VERSION 5.7 ;
BUSBITCHARS "[]" ;
DIVIDERCHAR "/" ;

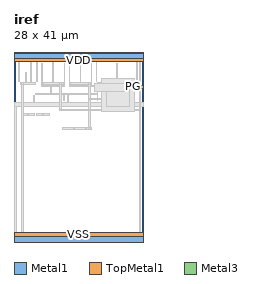
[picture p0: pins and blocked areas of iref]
MACRO iref
  CLASS BLOCK ;
  FOREIGN iref ;
  ORIGIN 0.000 0.000 ;
  SIZE 28.000 BY 41.000 ;
  PIN VDD
    DIRECTION INOUT ;
    USE POWER ;
    PORT
      LAYER Metal1 ;
        RECT 0.000 39.500 28.000 40.700 ;
      LAYER TopMetal1 ;
        RECT 0.000 39.000 28.000 41.000 ;
    END
  END VDD
  PIN VSS
    DIRECTION INOUT ;
    USE GROUND ;
    PORT
      LAYER Metal1 ;
        RECT 0.000 0.000 28.000 1.200 ;
      LAYER TopMetal1 ;
        RECT 0.000 0.000 28.000 2.000 ;
    END
  END VSS
  PIN PG
    DIRECTION OUTPUT ;
    USE SIGNAL ;
    ANTENNADIFFAREA 2.28 ;
    PORT
      LAYER Metal3 ;
        RECT 27.400 33.200 28.000 33.700 ;
    END
  END PG
  OBS
      LAYER Metal1 ;
        RECT 1.610 1.770 2.070 2.070 ;
        RECT 2.410 1.770 3.670 2.070 ;
        RECT 4.010 1.770 5.270 2.070 ;
        RECT 5.610 1.770 6.870 2.070 ;
        RECT 7.210 1.200 7.670 2.070 ;
        RECT 10.520 1.200 11.480 2.070 ;
        RECT 11.820 1.770 14.080 2.070 ;
        RECT 14.420 1.770 16.680 2.070 ;
        RECT 18.110 1.200 18.570 2.070 ;
        RECT 18.910 1.770 20.170 2.070 ;
        RECT 20.510 1.770 21.770 2.070 ;
        RECT 22.110 1.770 23.370 2.070 ;
        RECT 23.710 1.770 24.970 2.070 ;
        RECT 25.310 1.770 26.570 2.070 ;
        RECT 26.910 1.770 27.370 2.070 ;
        RECT 10.520 24.330 12.780 24.630 ;
        RECT 13.120 24.330 15.380 24.630 ;
        RECT 15.720 24.330 16.680 24.630 ;
        RECT 1.610 27.330 2.870 27.630 ;
        RECT 3.210 27.330 4.470 27.630 ;
        RECT 4.810 27.330 6.070 27.630 ;
        RECT 6.410 27.330 7.670 27.630 ;
        RECT 9.850 28.330 10.150 28.630 ;
        RECT 18.110 28.330 19.370 28.630 ;
        RECT 19.710 28.330 20.970 28.630 ;
        RECT 21.310 28.330 22.570 28.630 ;
        RECT 22.910 28.330 24.170 28.630 ;
        RECT 24.510 28.330 25.770 28.630 ;
        RECT 26.110 28.330 27.370 28.630 ;
        RECT 0.000 1.200 0.600 29.300 ;
        RECT 0.000 29.300 28.000 30.100 ;
        RECT 4.270 30.100 4.430 31.600 ;
        RECT 11.570 30.100 11.730 31.600 ;
        RECT 10.650 30.600 10.810 31.850 ;
        RECT 4.640 31.850 17.740 32.150 ;
        RECT 19.370 30.600 19.530 30.650 ;
        RECT 19.300 30.650 19.600 30.950 ;
        RECT 19.370 30.950 19.530 32.600 ;
        RECT 20.750 30.600 20.910 31.850 ;
        RECT 20.680 31.850 20.980 32.150 ;
        RECT 20.750 32.150 20.910 32.600 ;
        RECT 22.130 30.600 22.290 30.650 ;
        RECT 22.060 30.650 22.360 30.950 ;
        RECT 22.130 30.950 22.290 32.600 ;
        RECT 17.950 30.600 18.110 32.850 ;
        RECT 17.880 32.850 21.920 33.150 ;
        RECT 6.400 34.050 10.580 34.350 ;
        RECT 12.260 34.050 16.450 34.350 ;
        RECT 1.440 34.050 4.720 34.350 ;
        RECT 2.450 34.350 2.610 36.600 ;
        RECT 6.030 33.550 10.950 33.850 ;
        RECT 6.030 33.850 6.190 38.600 ;
        RECT 10.790 33.850 10.950 38.600 ;
        RECT 11.890 33.550 18.200 33.850 ;
        RECT 11.890 33.850 12.050 38.600 ;
        RECT 16.650 33.850 16.810 38.600 ;
        RECT 18.120 34.050 26.300 34.350 ;
        RECT 22.130 34.350 22.290 38.600 ;
        RECT 4.930 34.600 5.090 38.900 ;
        RECT 8.410 34.600 8.570 38.900 ;
        RECT 14.270 34.600 14.430 38.900 ;
        RECT 4.930 38.900 14.430 39.200 ;
        RECT 1.070 34.600 1.230 39.500 ;
        RECT 3.550 34.600 3.710 39.500 ;
        RECT 17.750 34.600 17.910 39.500 ;
        RECT 26.510 34.600 26.670 39.500 ;
      LAYER Metal2 ;
        RECT 2.300 0.700 2.700 1.100 ;
        RECT 6.300 0.700 6.700 1.100 ;
        RECT 10.300 0.700 10.700 1.100 ;
        RECT 14.300 0.700 14.700 1.100 ;
        RECT 18.300 0.700 18.700 1.100 ;
        RECT 22.300 0.700 22.700 1.100 ;
        RECT 26.300 0.700 26.700 1.100 ;
        RECT 20.140 28.280 20.540 28.680 ;
        RECT 22.800 29.500 23.200 29.900 ;
        RECT 24.800 29.500 25.200 29.900 ;
        RECT 7.800 31.800 8.200 32.200 ;
        RECT 7.850 32.200 8.150 33.500 ;
        RECT 7.800 33.500 8.200 33.900 ;
        RECT 17.830 32.800 18.230 33.900 ;
        RECT 1.640 1.720 2.040 2.120 ;
        RECT 1.690 2.120 1.990 34.000 ;
        RECT 1.640 34.000 2.040 34.400 ;
        RECT 9.800 28.280 10.200 28.680 ;
        RECT 9.850 28.680 10.150 34.000 ;
        RECT 9.800 34.000 10.200 34.400 ;
        RECT 16.100 24.280 16.500 24.680 ;
        RECT 16.150 24.680 16.450 30.650 ;
        RECT 19.250 30.600 19.650 30.650 ;
        RECT 22.010 30.600 22.410 30.650 ;
        RECT 16.150 30.650 22.410 30.950 ;
        RECT 19.250 30.950 19.650 31.000 ;
        RECT 22.010 30.950 22.410 31.000 ;
        RECT 16.150 30.950 16.450 34.000 ;
        RECT 16.100 34.000 16.500 34.400 ;
        RECT 20.630 31.800 21.030 32.200 ;
        RECT 20.680 32.200 20.980 33.250 ;
        RECT 20.630 33.250 21.030 33.650 ;
        RECT 20.680 33.650 20.980 34.000 ;
        RECT 20.630 34.000 21.030 34.400 ;
        RECT 2.300 39.900 2.700 40.300 ;
        RECT 6.300 39.900 6.700 40.300 ;
        RECT 10.300 39.900 10.700 40.300 ;
        RECT 14.300 39.900 14.700 40.300 ;
        RECT 18.300 39.900 18.700 40.300 ;
        RECT 22.300 39.900 22.700 40.300 ;
        RECT 26.300 39.900 26.700 40.300 ;
        RECT 26.940 1.720 27.340 2.120 ;
        RECT 26.990 2.120 27.290 39.900 ;
        RECT 26.940 39.900 27.340 40.300 ;
      LAYER Metal3 ;
        RECT 2.300 0.700 2.700 1.100 ;
        RECT 6.300 0.700 6.700 1.100 ;
        RECT 10.300 0.700 10.700 1.100 ;
        RECT 14.300 0.700 14.700 1.100 ;
        RECT 18.300 0.700 18.700 1.100 ;
        RECT 22.300 0.700 22.700 1.100 ;
        RECT 26.300 0.700 26.700 1.100 ;
        RECT 9.800 28.280 20.540 28.680 ;
        RECT 22.800 29.500 23.200 29.900 ;
        RECT 24.800 29.500 25.200 29.900 ;
        RECT 17.830 33.150 18.230 33.550 ;
        RECT 20.630 33.200 27.400 33.700 ;
        RECT 2.300 39.900 2.700 40.300 ;
        RECT 6.300 39.900 6.700 40.300 ;
        RECT 10.300 39.900 10.700 40.300 ;
        RECT 14.300 39.900 14.700 40.300 ;
        RECT 18.300 39.900 18.700 40.300 ;
        RECT 22.300 39.900 22.700 40.300 ;
        RECT 26.300 39.900 26.700 40.300 ;
      LAYER Metal4 ;
        RECT 2.300 0.700 2.700 1.100 ;
        RECT 6.300 0.700 6.700 1.100 ;
        RECT 10.300 0.700 10.700 1.100 ;
        RECT 14.300 0.700 14.700 1.100 ;
        RECT 18.300 0.700 18.700 1.100 ;
        RECT 22.300 0.700 22.700 1.100 ;
        RECT 26.300 0.700 26.700 1.100 ;
        RECT 22.800 29.500 23.200 29.900 ;
        RECT 24.800 29.500 25.200 29.900 ;
        RECT 17.830 33.150 18.230 33.550 ;
        RECT 2.300 39.900 2.700 40.300 ;
        RECT 6.300 39.900 6.700 40.300 ;
        RECT 10.300 39.900 10.700 40.300 ;
        RECT 14.300 39.900 14.700 40.300 ;
        RECT 18.300 39.900 18.700 40.300 ;
        RECT 22.300 39.900 22.700 40.300 ;
        RECT 26.300 39.900 26.700 40.300 ;
      LAYER Metal5 ;
        RECT 2.190 0.590 2.810 1.210 ;
        RECT 6.190 0.590 6.810 1.210 ;
        RECT 10.190 0.590 10.810 1.210 ;
        RECT 14.190 0.590 14.810 1.210 ;
        RECT 18.190 0.590 18.810 1.210 ;
        RECT 22.190 0.590 22.810 1.210 ;
        RECT 26.190 0.590 26.810 1.210 ;
        RECT 17.720 33.040 18.340 33.660 ;
        RECT 18.800 28.100 26.000 35.300 ;
        RECT 2.190 39.790 2.810 40.410 ;
        RECT 6.190 39.790 6.810 40.410 ;
        RECT 10.190 39.790 10.810 40.410 ;
        RECT 14.190 39.790 14.810 40.410 ;
        RECT 18.190 39.790 18.810 40.410 ;
        RECT 22.190 39.790 22.810 40.410 ;
        RECT 26.190 39.790 26.810 40.410 ;
      LAYER TopMetal1 ;
        RECT 19.880 29.180 24.920 32.500 ;
        RECT 17.400 32.500 24.920 34.200 ;
        RECT 19.880 34.200 24.920 34.220 ;
  END
END iref

END LIBRARY
